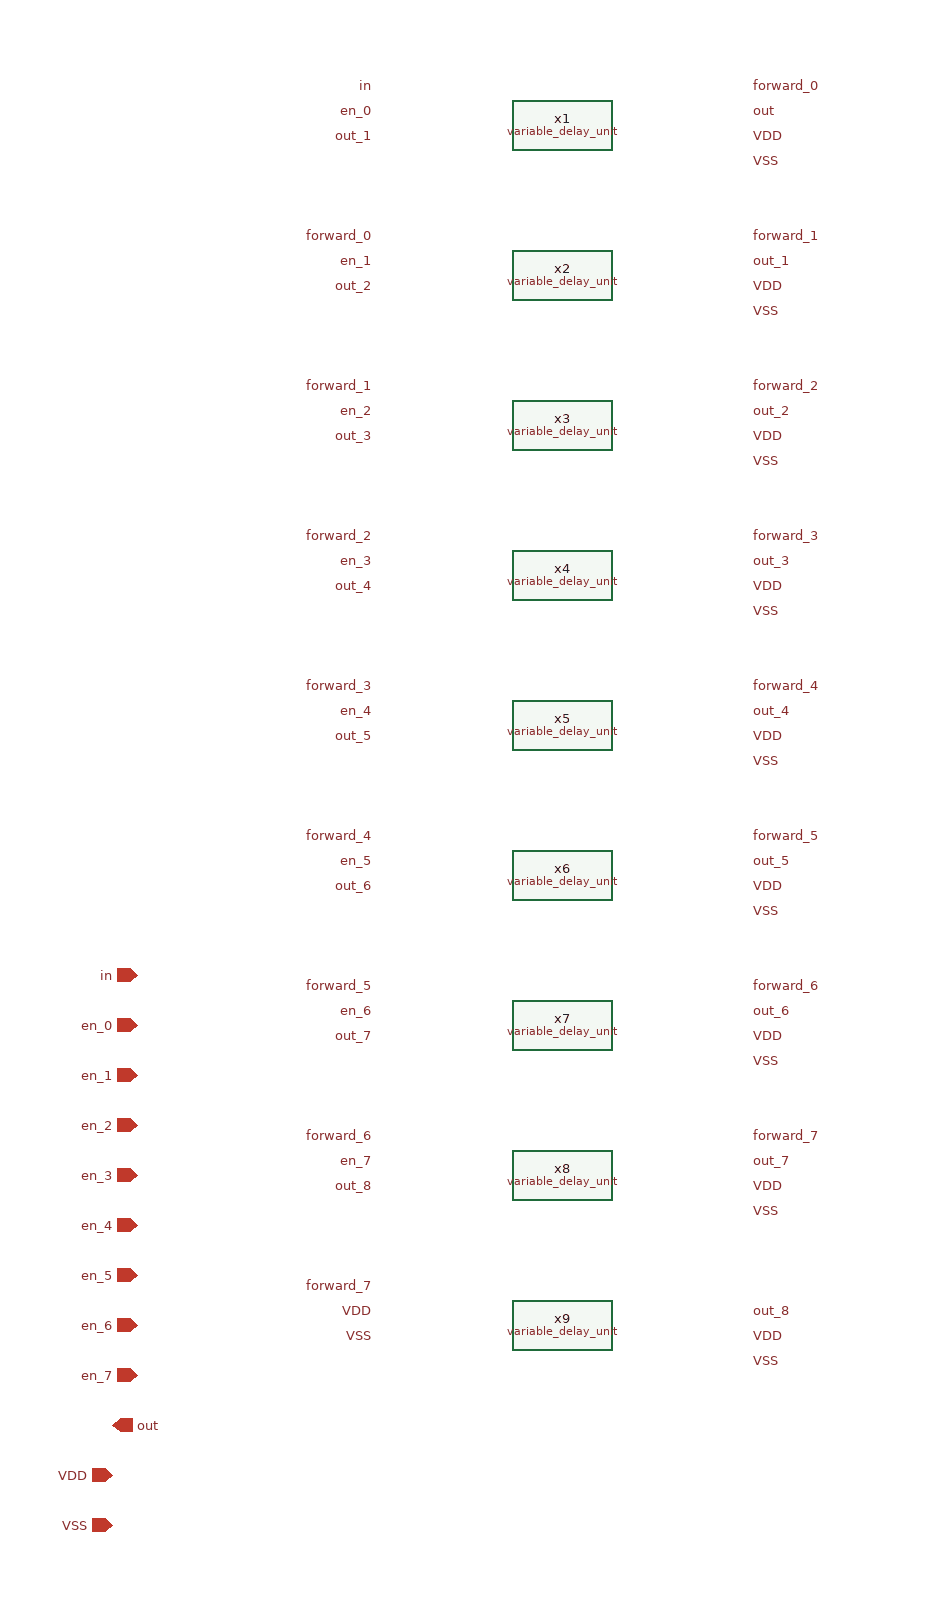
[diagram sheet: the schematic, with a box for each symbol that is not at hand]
v {xschem version=3.4.5 file_version=1.2
}
G {}
K {}
V {}
S {}
E {}
C {devices/iopin.sym} 70 -80 0 0 {name=p1 lab=VDD}
C {devices/ipin.sym} 90 -480 0 0 {name=p3 lab=in}
C {devices/opin.sym} 70 -120 0 0 {name=p5 lab=out}
C {devices/iopin.sym} 70 -40 0 0 {name=p2 lab=VSS}
C {devices/ipin.sym} 90 -440 0 0 {name=p13 lab=en_0}
C {variable_delay_unit.sym} 430 -1160 0 0 {name=x1}
C {devices/lab_pin.sym} 580 -1150 0 1 {name=p10 sig_type=std_logic lab=VDD}
C {devices/lab_pin.sym} 580 -1130 0 1 {name=p4 sig_type=std_logic lab=VSS}
C {devices/lab_pin.sym} 280 -1170 0 0 {name=p6 sig_type=std_logic lab=en_0}
C {devices/lab_pin.sym} 580 -1170 0 1 {name=p7 sig_type=std_logic lab=out}
C {devices/lab_pin.sym} 280 -1190 0 0 {name=p8 sig_type=std_logic lab=in}
C {variable_delay_unit.sym} 430 -1040 0 0 {name=x2}
C {devices/lab_pin.sym} 580 -1030 0 1 {name=p9 sig_type=std_logic lab=VDD}
C {devices/lab_pin.sym} 580 -1010 0 1 {name=p11 sig_type=std_logic lab=VSS}
C {devices/lab_pin.sym} 280 -1050 0 0 {name=p12 sig_type=std_logic lab=en_1}
C {devices/lab_pin.sym} 580 -1050 0 1 {name=p14 sig_type=std_logic lab=out_1}
C {devices/lab_pin.sym} 580 -1190 0 1 {name=p16 sig_type=std_logic lab=forward_0}
C {devices/lab_pin.sym} 280 -1070 0 0 {name=p15 sig_type=std_logic lab=forward_0}
C {devices/ipin.sym} 90 -400 0 0 {name=p17 lab=en_1}
C {devices/lab_pin.sym} 280 -1150 0 0 {name=p18 sig_type=std_logic lab=out_1}
C {devices/lab_pin.sym} 580 -1070 0 1 {name=p19 sig_type=std_logic lab=forward_1}
C {variable_delay_unit.sym} 430 -920 0 0 {name=x3}
C {devices/lab_pin.sym} 580 -910 0 1 {name=p20 sig_type=std_logic lab=VDD}
C {devices/lab_pin.sym} 580 -890 0 1 {name=p21 sig_type=std_logic lab=VSS}
C {devices/lab_pin.sym} 280 -930 0 0 {name=p22 sig_type=std_logic lab=en_2}
C {devices/lab_pin.sym} 580 -930 0 1 {name=p23 sig_type=std_logic lab=out_2}
C {devices/lab_pin.sym} 280 -950 0 0 {name=p24 sig_type=std_logic lab=forward_1}
C {devices/lab_pin.sym} 580 -950 0 1 {name=p25 sig_type=std_logic lab=forward_2}
C {devices/lab_pin.sym} 280 -1030 0 0 {name=p26 sig_type=std_logic lab=out_2}
C {variable_delay_unit.sym} 430 -800 0 0 {name=x4}
C {devices/lab_pin.sym} 580 -790 0 1 {name=p27 sig_type=std_logic lab=VDD}
C {devices/lab_pin.sym} 580 -770 0 1 {name=p28 sig_type=std_logic lab=VSS}
C {devices/lab_pin.sym} 280 -810 0 0 {name=p29 sig_type=std_logic lab=en_3}
C {devices/lab_pin.sym} 580 -810 0 1 {name=p30 sig_type=std_logic lab=out_3}
C {devices/lab_pin.sym} 280 -830 0 0 {name=p31 sig_type=std_logic lab=forward_2}
C {devices/lab_pin.sym} 580 -830 0 1 {name=p32 sig_type=std_logic lab=forward_3}
C {devices/lab_pin.sym} 280 -910 0 0 {name=p33 sig_type=std_logic lab=out_3}
C {variable_delay_unit.sym} 430 -680 0 0 {name=x5}
C {devices/lab_pin.sym} 580 -670 0 1 {name=p34 sig_type=std_logic lab=VDD}
C {devices/lab_pin.sym} 580 -650 0 1 {name=p35 sig_type=std_logic lab=VSS}
C {devices/lab_pin.sym} 280 -690 0 0 {name=p36 sig_type=std_logic lab=en_4}
C {devices/lab_pin.sym} 580 -690 0 1 {name=p37 sig_type=std_logic lab=out_4}
C {devices/lab_pin.sym} 280 -710 0 0 {name=p38 sig_type=std_logic lab=forward_3}
C {devices/lab_pin.sym} 580 -710 0 1 {name=p39 sig_type=std_logic lab=forward_4}
C {devices/lab_pin.sym} 280 -790 0 0 {name=p40 sig_type=std_logic lab=out_4}
C {variable_delay_unit.sym} 430 -560 0 0 {name=x6}
C {devices/lab_pin.sym} 580 -550 0 1 {name=p41 sig_type=std_logic lab=VDD}
C {devices/lab_pin.sym} 580 -530 0 1 {name=p42 sig_type=std_logic lab=VSS}
C {devices/lab_pin.sym} 280 -570 0 0 {name=p43 sig_type=std_logic lab=en_5}
C {devices/lab_pin.sym} 580 -570 0 1 {name=p44 sig_type=std_logic lab=out_5}
C {devices/lab_pin.sym} 280 -590 0 0 {name=p45 sig_type=std_logic lab=forward_4}
C {devices/lab_pin.sym} 580 -590 0 1 {name=p46 sig_type=std_logic lab=forward_5}
C {variable_delay_unit.sym} 430 -440 0 0 {name=x7}
C {devices/lab_pin.sym} 580 -430 0 1 {name=p47 sig_type=std_logic lab=VDD}
C {devices/lab_pin.sym} 580 -410 0 1 {name=p48 sig_type=std_logic lab=VSS}
C {devices/lab_pin.sym} 280 -450 0 0 {name=p49 sig_type=std_logic lab=en_6}
C {devices/lab_pin.sym} 580 -450 0 1 {name=p50 sig_type=std_logic lab=out_6}
C {devices/lab_pin.sym} 280 -470 0 0 {name=p51 sig_type=std_logic lab=forward_5}
C {devices/lab_pin.sym} 580 -470 0 1 {name=p52 sig_type=std_logic lab=forward_6}
C {devices/lab_pin.sym} 280 -550 0 0 {name=p53 sig_type=std_logic lab=out_6}
C {devices/lab_pin.sym} 280 -670 0 0 {name=p54 sig_type=std_logic lab=out_5}
C {variable_delay_unit.sym} 430 -320 0 0 {name=x8}
C {devices/lab_pin.sym} 580 -310 0 1 {name=p55 sig_type=std_logic lab=VDD}
C {devices/lab_pin.sym} 580 -290 0 1 {name=p56 sig_type=std_logic lab=VSS}
C {devices/lab_pin.sym} 280 -330 0 0 {name=p57 sig_type=std_logic lab=en_7}
C {devices/lab_pin.sym} 580 -330 0 1 {name=p58 sig_type=std_logic lab=out_7}
C {devices/lab_pin.sym} 280 -350 0 0 {name=p59 sig_type=std_logic lab=forward_6}
C {devices/lab_pin.sym} 580 -350 0 1 {name=p60 sig_type=std_logic lab=forward_7}
C {devices/lab_pin.sym} 280 -430 0 0 {name=p61 sig_type=std_logic lab=out_7}
C {devices/ipin.sym} 90 -360 0 0 {name=p62 lab=en_2}
C {devices/ipin.sym} 90 -320 0 0 {name=p63 lab=en_3}
C {devices/ipin.sym} 90 -280 0 0 {name=p64 lab=en_4}
C {devices/ipin.sym} 90 -240 0 0 {name=p65 lab=en_5}
C {devices/ipin.sym} 90 -200 0 0 {name=p66 lab=en_6}
C {devices/ipin.sym} 90 -160 0 0 {name=p67 lab=en_7}
C {devices/lab_pin.sym} 280 -310 0 0 {name=p74 sig_type=std_logic lab=out_8}
C {variable_delay_unit.sym} 430 -200 0 0 {name=x9}
C {devices/lab_pin.sym} 580 -190 0 1 {name=p68 sig_type=std_logic lab=VDD}
C {devices/lab_pin.sym} 580 -170 0 1 {name=p69 sig_type=std_logic lab=VSS}
C {devices/lab_pin.sym} 580 -210 0 1 {name=p71 sig_type=std_logic lab=out_8}
C {devices/lab_pin.sym} 280 -230 0 0 {name=p72 sig_type=std_logic lab=forward_7}
C {devices/lab_pin.sym} 280 -210 0 0 {name=p70 sig_type=std_logic lab=VDD}
C {devices/lab_pin.sym} 280 -190 0 0 {name=p75 sig_type=std_logic lab=VSS}
